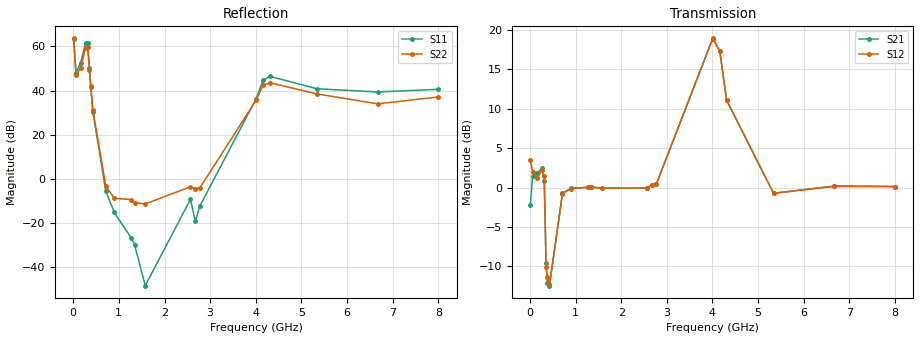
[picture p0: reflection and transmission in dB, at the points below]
!Agilent Technologies,N5230A,US43500312,A.07.50.67
!Agilent N5230A: A.07.50.67
!Date: Tuesday, June 09, 2015 15:37:51
!Correction: S11(Full 2 Port(1,2))
!S21(Full 2 Port(1,2))
!S12(Full 2 Port(1,2))
!S22(Full 2 Port(1,2))
!S2P File: Measurements: S11, S21, S12, S22:
# Hz S  MA  R 50
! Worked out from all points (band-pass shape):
!   1601 points, 10 MHz to 8 GHz, reference 50 ohm
!   highest |S21| = 18.92 dB at 4.005 GHz (marker M1); lowest = -12.5 dB at 429.5 MHz (marker M2)
!   |S21| within 3 dB of the highest: 3.837 GHz to 4.205 GHz (367.7 MHz wide, 9.14 % of centre)
!   lowest |S11| = -48.3 dB at 1.578 GHz (marker M3), VSWR 1.01, Z = 50.1 + j0.371 ohm
!   |S11| at or under -10 dB: 847.4 MHz to 2.118 GHz (1.27 GHz wide, 85.7 % of centre); 2.584 GHz to 2.795 GHz (211.3 MHz wide, 7.86 % of centre); 3.343 GHz to 3.409 GHz (66.3 MHz wide, 1.96 % of centre)
!   |S22| runs from -13.4 to 63.6 dB; largest |S21 - S12| = 0.72
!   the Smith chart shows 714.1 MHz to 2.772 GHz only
!   S11 on the Smith chart (normalised r, x): 714.1 MHz: 0.31, -0.10; 898.9 MHz: 0.87, -0.30; 1.268 GHz: 1.10, +0.02; 2.567 GHz: 0.53, -0.27; 2.772 GHz: 1.62, +0.14
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1e7  1493 171.2  0.7782 -27.0  1.497 -25.0  1519 -19.4
5.99375e7  255.2 327.7  1.189 2.6  1.257 -5.8  229.1 92.7
1.648062e8  428.4 406.2  1.239 8.2  1.15 6.2  321.3 127.2
2.69675e8  1217 393.6  1.328 -1.5  1.302 -1.4  933.2 109.0
3.146188e8  1218 433.6  1.097 47.9  1.178 47.1  993.6 153.9
3.545688e8  325.3 455.3  0.3301 53.7  0.311 50.1  289.8 184.1
3.845312e8  124.9 454.1  0.247 36.0  0.2701 32.3  120.7 191.9
4.29475e8  33.21 452.6  0.2381 35.2  0.2438 33.7  37.24 209.0
7.141188e8  0.5356 552.3  0.9219 74.2  0.915 74.2  0.6902 443.8
8.988875e8  0.175 615.9  0.9882 64.5  0.9842 64.4  0.3657 533.1
1.268425e9  0.0466 730.7  1.004 65.4  1.004 65.5  0.3423 722.1
1.343331e9  0.03278 881.9  1.008 65.9  1.008 65.9  0.2923 759.6
1.578038e9  0.003862 793.2  0.992 65.4  0.9912 65.4  0.2731 861.7
2.5668e9  0.3453 580.1  0.9916 68.3  0.9934 68.4  0.6673 1184.7
2.676662e9  0.1099 615.9  1.041 69.3  1.044 69.3  0.6082 1216.7
2.771544e9  0.2417 730.0  1.054 69.0  1.058 69.1  0.6231 1252.0
4.005e9  64.86 708.5  8.827 49.6  8.859 49.8  60.45 1528.7
4.159806e9  172.9 677.1  7.342 -4.7  7.374 -4.5  132.1 1494.6
4.309619e9  209.8 638.5  3.578 -45.7  3.595 -45.3  150.5 1454.6
5.338331e9  110.1 616.6  0.9201 11.1  0.9192 11.1  84.16 1407.8
6.671662e9  93.03 648.3  1.023 9.5  1.018 9.7  50.16 1347.5
8e9  106.9 672.2  1.015 7.0  1.015 6.7  71.95 1312.6
